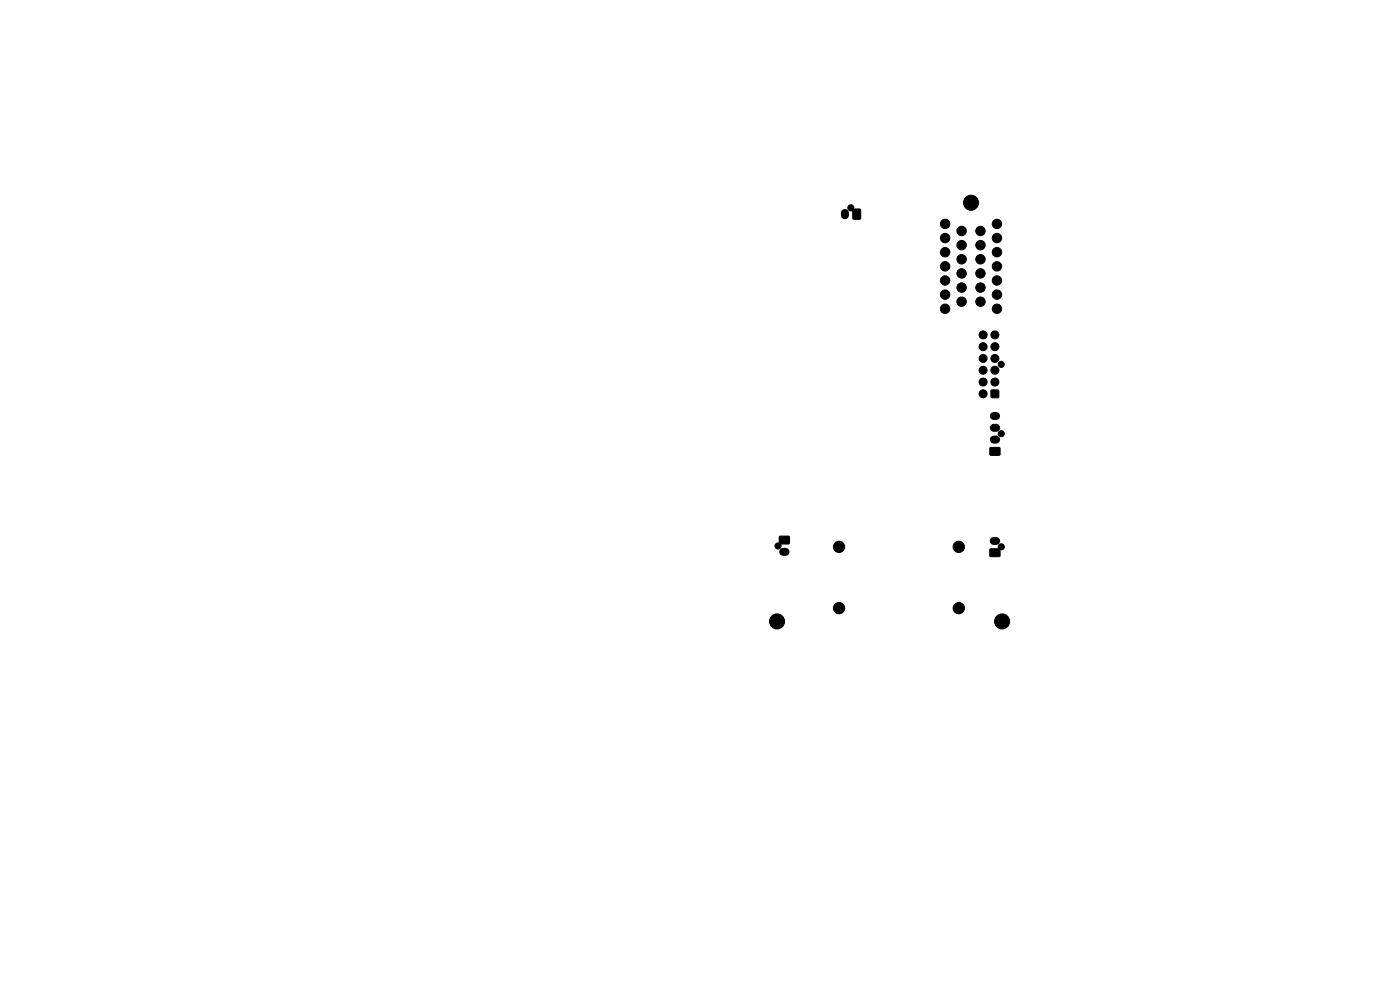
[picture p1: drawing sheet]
<svg xmlns="http://www.w3.org/2000/svg" width="297mm" height="210mm" viewBox="0 0 297 210" stroke-linecap="round" stroke-linejoin="round" font-family="sans-serif">
<g fill="#000" stroke="#000" stroke-width=".21">
<path d="M181 44.7l.4-.4 1.1 .1v2.1h-1.5zM210.3 82.8h1.5v1.5h-1.5zM210 95h2.1v1.5h-2.1zM165.4 113.8h2v1.5h-1.8l-.3-.4zM210 116.5h1.8l.4 .4-.1 1.1h-2.1z"/>
<circle cx="180.5" cy="44.1" r=".65"/>
<circle cx="200.5" cy="53.5" r="1"/>
<circle cx="200.5" cy="59.5" r="1"/>
<circle cx="200.5" cy="50.5" r="1"/>
<circle cx="200.5" cy="56.5" r="1"/>
<circle cx="200.5" cy="47.5" r="1"/>
<circle cx="204" cy="55" r="1"/>
<circle cx="204" cy="49" r="1"/>
<circle cx="204" cy="52" r="1"/>
<circle cx="204" cy="58" r="1"/>
<circle cx="206" cy="43" r="1.6"/>
<circle cx="208" cy="49" r="1"/>
<circle cx="208" cy="55" r="1"/>
<circle cx="208" cy="52" r="1"/>
<circle cx="208" cy="58" r="1"/>
<circle cx="211.5" cy="59.5" r="1"/>
<circle cx="211.5" cy="53.5" r="1"/>
<circle cx="211.5" cy="50.5" r="1"/>
<circle cx="211.5" cy="56.5" r="1"/>
<circle cx="211.5" cy="47.5" r="1"/>
<circle cx="200.5" cy="62.5" r="1"/>
<circle cx="200.5" cy="65.5" r="1"/>
<circle cx="204" cy="61" r="1"/>
<circle cx="204" cy="64" r="1"/>
<circle cx="208" cy="61" r="1"/>
<circle cx="208" cy="64" r="1"/>
<circle cx="208.6" cy="76" r=".85"/>
<circle cx="208.6" cy="73.5" r=".85"/>
<circle cx="208.6" cy="78.5" r=".85"/>
<circle cx="208.6" cy="71" r=".85"/>
<circle cx="211.1" cy="76" r=".85"/>
<circle cx="211.1" cy="73.5" r=".85"/>
<circle cx="211.1" cy="78.5" r=".85"/>
<circle cx="211.1" cy="71" r=".85"/>
<circle cx="211.5" cy="62.5" r="1"/>
<circle cx="211.5" cy="65.5" r="1"/>
<circle cx="212.4" cy="77.3" r=".65"/>
<circle cx="208.6" cy="81" r=".85"/>
<circle cx="208.6" cy="83.5" r=".85"/>
<circle cx="211.1" cy="81" r=".85"/>
<circle cx="212.4" cy="92" r=".65"/>
<circle cx="165.1" cy="115.8" r=".65"/>
<circle cx="178" cy="116" r="1.2"/>
<circle cx="203.4" cy="116" r="1.2"/>
<circle cx="212.4" cy="116" r=".65"/>
<circle cx="164.8" cy="131.8" r="1.6"/>
<circle cx="178" cy="129" r="1.2"/>
<circle cx="203.4" cy="129" r="1.2"/>
<circle cx="212.6" cy="131.8" r="1.6"/>
</g>
<path d="M179.2 45.2v.5M210.8 93.3h.5M210.8 90.8h.5M210.8 88.3h.5M166.1 117.1h.5M210.8 114.8h.5" fill="none" stroke="#000" stroke-width="1.7"/>
</svg>
